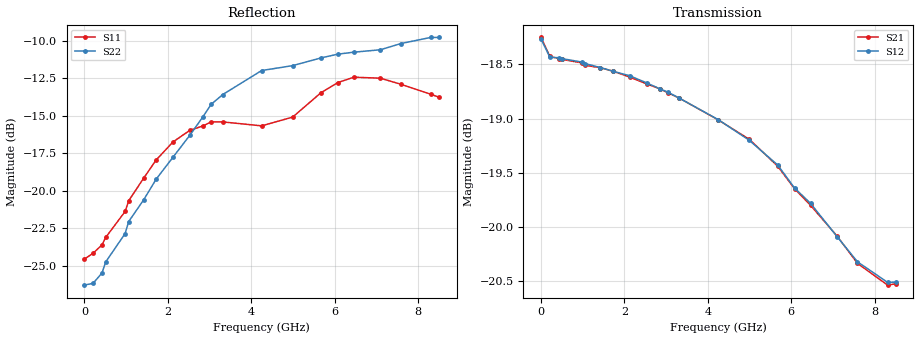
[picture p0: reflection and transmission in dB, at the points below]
! device id: pe43620
! dir: c:\dsa\pe43620\data\pe43620\025c\3p300v\18p00db
! Serial: 1001
! Insertion: A
! Temp: 25C
! VDD: 3.300V
! Attenuation Step: 18.00dB
! IDD: 7.937165e-03mA
! FILE NAME
! DATE 10-22-2008 14:03:49
! CORRECTED  DATA
#  Hz  S  RI  R  50.00
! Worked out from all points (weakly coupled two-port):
!   401 points, 300 kHz to 8.5 GHz, reference 50 ohm
!   highest |S21| = -18.25 dB at 300 kHz (marker M1); lowest = -20.5 dB at 8.309 GHz (marker M2)
!   lowest |S11| = -24.5 dB at 300 kHz (marker M3), VSWR 1.13, Z = 44.4 + j0.000979 ohm
!   |S11| at or under -10 dB: start of sweep to end of sweep
!   |S22| runs from -26.3 to -9.7 dB; largest |S21 - S12| = 0.00066
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300000  -0.0592 1.1e-05  0.1223 -0.000509  0.1221 -0.000291  -0.0485 -0.000399
2.127925e8  -0.062 -0.000335  0.1198 -0.00347  0.1197 -0.00344  -0.0485 -0.00819
4.25285e8  -0.0661 -0.00091  0.1194 -0.00659  0.1195 -0.00663  -0.0507 -0.0165
5.10282e8  -0.0699 -0.00175  0.1192 -0.00792  0.1193 -0.00803  -0.0544 -0.0198
9.777655e8  -0.0846 -0.0116  0.1181 -0.0149  0.1182 -0.0149  -0.0609 -0.0385
1.062763e9  -0.0915 -0.0146  0.1176 -0.0163  0.1178 -0.0164  -0.066 -0.0434
1.424e9  -0.1067 -0.0282  0.1164 -0.0218  0.1164 -0.0219  -0.0768 -0.0532
1.721489e9  -0.1183 -0.0455  0.115 -0.0264  0.115 -0.0264  -0.0891 -0.0635
2.125225e9  -0.1281 -0.0692  0.1126 -0.0327  0.1128 -0.0326  -0.1069 -0.0731
2.528961e9  -0.1322 -0.0887  0.1099 -0.0384  0.11 -0.0385  -0.1319 -0.078
2.8477e9  -0.1313 -0.0995  0.1076 -0.0428  0.1076 -0.0428  -0.1561 -0.0834
3.038943e9  -0.1328 -0.1059  0.106 -0.0454  0.1061 -0.0454  -0.1707 -0.0928
3.315183e9  -0.1309 -0.1082  0.1038 -0.0487  0.1038 -0.0487  -0.1836 -0.1007
4.25015e9  -0.1394 -0.0878  0.0953 -0.0589  0.0954 -0.0588  -0.2282 -0.1067
4.993874e9  -0.1647 -0.0626  0.0888 -0.0645  0.0885 -0.0647  -0.2486 -0.0815
5.67385e9  -0.2044 -0.0584  0.0809 -0.0695  0.081 -0.0696  -0.274 -0.0444
6.077586e9  -0.222 -0.0589  0.0759 -0.0713  0.0762 -0.0711  -0.2849 -0.0205
6.460072e9  -0.2319 -0.0593  0.0715 -0.0732  0.0718 -0.0732  -0.29 0.00629
7.09755e9  -0.2321 -0.0506  0.0636 -0.0759  0.0634 -0.076  -0.2899 0.0572
7.586282e9  -0.2243 -0.0331  0.0578 -0.0769  0.0578 -0.0771  -0.2939 0.0983
8.308757e9  -0.2098 0.00747  0.0532 -0.0775  0.0531 -0.0779  -0.2939 0.1386
8.5e9  -0.2046 0.0165  0.0524 -0.0782  0.0524 -0.0784  -0.2877 0.1508
